VERSION 5.8 ;
BUSBITCHARS "[]" ;
DIVIDERCHAR "/" ;
UNITS
    DATABASE MICRONS 1000 ;
END UNITS

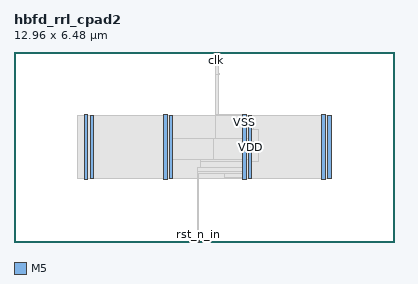
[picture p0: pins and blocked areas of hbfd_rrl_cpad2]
MACRO hbfd_rrl_cpad2
  FOREIGN hbfd_rrl_cpad2 0 0 ;
  CLASS BLOCK ;
  SIZE 12.96 BY 6.48 ;
  PIN clk
    DIRECTION INPUT ;
    USE SIGNAL ;
    PORT
      LAYER M5 ;
        RECT  6.864 6.396 6.888 6.48 ;
    END
  END clk
  PIN rst_n
    DIRECTION OUTPUT ;
    USE SIGNAL ;
    PORT
      LAYER M5 ;
        RECT  6.96 6.396 6.984 6.48 ;
    END
  END rst_n
  PIN rst_n_in
    DIRECTION INPUT ;
    USE SIGNAL ;
    PORT
      LAYER M5 ;
        RECT  6.288 0 6.312 0.084 ;
    END
    PORT
      LAYER M5 ;
        RECT  6.288 0.016 6.312 0.131 ;
    END
  END rst_n_in
  PIN VDD
    DIRECTION INOUT ;
    USE POWER ;
    PORT
      LAYER M5 ;
        RECT  10.692 2.151 10.812 4.329 ;
        RECT  7.992 2.151 8.112 4.329 ;
        RECT  5.292 2.151 5.412 4.329 ;
        RECT  2.592 2.151 2.712 4.329 ;
    END
  END VDD
  PIN VSS
    DIRECTION INOUT ;
    USE GROUND ;
    PORT
      LAYER M5 ;
        RECT  10.5 2.137 10.62 4.343 ;
        RECT  7.8 2.137 7.92 4.343 ;
        RECT  5.1 2.137 5.22 4.343 ;
        RECT  2.4 2.137 2.52 4.343 ;
    END
  END VSS
  # OT_OBS_CLOSED layer=M5 d_um=1.536 added=3
  OBS
    LAYER RVTN ;
     RECT  2.16 2.16 10.8 2.295 ;
     RECT  2.16 2.565 10.8 2.835 ;
     RECT  2.16 3.105 10.8 3.375 ;
     RECT  2.16 3.645 10.8 3.915 ;
     RECT  2.16 4.185 10.8 4.32 ;
    LAYER RVTP ;
     RECT  2.16 2.295 10.8 2.565 ;
     RECT  2.16 2.835 10.8 3.105 ;
     RECT  2.16 3.375 10.8 3.645 ;
     RECT  2.16 3.915 10.8 4.185 ;
    LAYER M1 ;
     RECT  2.16 2.151 10.8 4.329 ;
    LAYER M2 ;
     RECT  2.16 2.151 10.8 4.329 ;
     RECT  10.8 2.421 10.812 4.059 ;
    LAYER M3 ;
     RECT  7.815 2.143 7.905 2.191 ;
     RECT  6.264 0.091 6.282 2.335 ;
     RECT  7.164 2.191 7.905 2.335 ;
     RECT  2.415 2.143 2.505 2.413 ;
     RECT  5.115 2.143 5.205 2.413 ;
     RECT  6.264 2.335 7.905 2.413 ;
     RECT  10.515 2.143 10.605 2.413 ;
     RECT  6.264 2.413 8.097 2.525 ;
     RECT  6.372 2.525 8.097 2.731 ;
     RECT  6.372 2.731 8.334 3.415 ;
     RECT  6.192 3.415 8.334 3.839 ;
     RECT  7.668 3.839 8.154 3.911 ;
     RECT  6.624 3.839 6.894 3.965 ;
     RECT  2.415 2.413 2.697 4.067 ;
     RECT  5.115 2.413 5.397 4.067 ;
     RECT  10.515 2.413 10.797 4.067 ;
     RECT  7.815 3.911 8.154 4.109 ;
     RECT  6.66 3.965 6.894 4.289 ;
     RECT  7.815 4.109 8.01 4.289 ;
     RECT  2.415 4.067 2.505 4.337 ;
     RECT  5.115 4.067 5.205 4.337 ;
     RECT  7.815 4.289 7.905 4.337 ;
     RECT  10.515 4.067 10.605 4.337 ;
     RECT  6.876 4.289 6.894 5.741 ;
    LAYER M4 ;
     RECT  2.408 2.148 2.512 4.332 ;
     RECT  2.512 2.418 2.704 4.062 ;
     RECT  5.108 2.148 5.212 4.332 ;
     RECT  5.212 2.418 5.404 4.062 ;
     RECT  6.253 0.096 6.337 0.12 ;
     RECT  6.613 3.936 6.764 3.96 ;
     RECT  6.764 3.504 6.805 3.96 ;
     RECT  6.865 5.712 6.995 5.736 ;
     RECT  6.805 2.832 7.808 3.96 ;
     RECT  7.808 2.148 7.912 4.332 ;
     RECT  7.912 2.418 8.104 4.062 ;
     RECT  10.508 2.148 10.612 4.332 ;
     RECT  10.612 2.418 10.804 4.062 ;
    LAYER M5 ;
     RECT  2.4 2.137 2.52 2.151 ;
     RECT  5.1 2.137 5.22 2.151 ;
     RECT  7.8 2.137 7.92 2.151 ;
     RECT  10.5 2.137 10.62 2.151 ;
     RECT  7.8 2.151 8.112 2.821 ;
     RECT  6.816 2.821 8.112 3.539 ;
     RECT  2.4 2.151 2.712 4.329 ;
     RECT  5.1 2.151 5.412 4.329 ;
     RECT  6.864 3.539 8.112 4.329 ;
     RECT  10.5 2.151 10.812 4.329 ;
     RECT  2.4 4.329 2.52 4.343 ;
     RECT  5.1 4.329 5.22 4.343 ;
     RECT  6.864 4.329 7.92 4.343 ;
     RECT  10.5 4.329 10.62 4.343 ;
     RECT  6.864 4.343 6.888 5.701 ;
     RECT  6.864 5.701 6.984 6.396 ;
     RECT  6.888 6.396 6.96 6.416 ;
     RECT  5.412 2.821 6.816 3.539 ;
     RECT  5.412 3.539 6.864 4.329 ;
     RECT  6.888 4.343 6.984 5.701 ;
  END
END hbfd_rrl_cpad2
END LIBRARY
